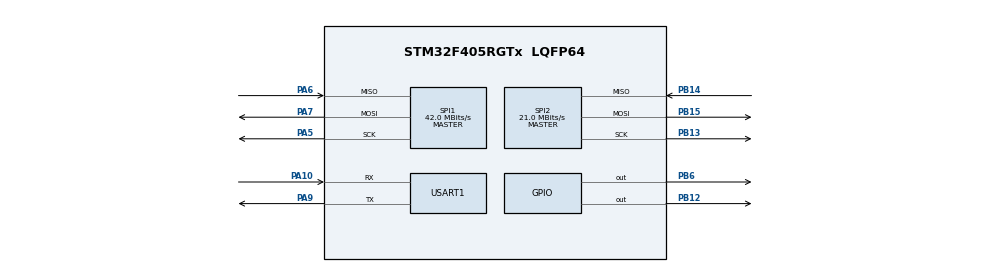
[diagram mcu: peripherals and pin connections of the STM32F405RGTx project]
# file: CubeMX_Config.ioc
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Mcu.Family=STM32F4
Mcu.Name=STM32F405RGTx
Mcu.Package=LQFP64
NVIC.PriorityGroup=NVIC_PRIORITYGROUP_4
PA10.Mode=Asynchronous
PA10.Signal=USART1_RX
PA13.Mode=Serial_Wire
PA13.Signal=SYS_JTMS-SWDIO
PA14.Mode=Serial_Wire
PA14.Signal=SYS_JTCK-SWCLK
PA5.Mode=Full_Duplex_Master
PA5.Signal=SPI1_SCK
PA6.Mode=Full_Duplex_Master
PA6.Signal=SPI1_MISO
PA7.Mode=Full_Duplex_Master
PA7.Signal=SPI1_MOSI
PA9.Mode=Asynchronous
PA9.Signal=USART1_TX
PB12.Signal=GPIO_Output
PB13.Mode=Full_Duplex_Master
PB13.Signal=SPI2_SCK
PB14.Mode=Full_Duplex_Master
PB14.Signal=SPI2_MISO
PB15.Mode=Full_Duplex_Master
PB15.Signal=SPI2_MOSI
PB6.Signal=GPIO_Output
PC14-OSC32_IN.Mode=LSE-External-Oscillator
PC14-OSC32_IN.Signal=RCC_OSC32_IN
PC15-OSC32_OUT.Mode=LSE-External-Oscillator
PC15-OSC32_OUT.Signal=RCC_OSC32_OUT
PH0-OSC_IN.Mode=HSE-External-Oscillator
PH0-OSC_IN.Signal=RCC_OSC_IN
PH1-OSC_OUT.Mode=HSE-External-Oscillator
PH1-OSC_OUT.Signal=RCC_OSC_OUT
ProjectManager.HeapSize=0x200
ProjectManager.StackSize=0x400
ProjectManager.TargetToolchain=MDK-ARM V5
RCC.48MHZClocksFreq_Value=84000000
RCC.AHBFreq_Value=168000000
RCC.APB1CLKDivider=RCC_HCLK_DIV4
RCC.APB1Freq_Value=42000000
RCC.APB1TimFreq_Value=84000000
RCC.APB2CLKDivider=RCC_HCLK_DIV2
RCC.APB2Freq_Value=84000000
RCC.APB2TimFreq_Value=168000000
RCC.CortexFreq_Value=168000000
RCC.HCLKFreq_Value=168000000
RCC.HSE_VALUE=8000000
RCC.HSI_VALUE=16000000
RCC.PLLM=4
RCC.PLLN=168
RCC.PLLSourceVirtual=RCC_PLLSOURCE_HSE
RCC.RCC_RTC_Clock_SourceVirtual=RCC_RTCCLKSOURCE_LSE
RCC.SYSCLKFreq_VALUE=168000000
RCC.SYSCLKSource=RCC_SYSCLKSOURCE_PLLCLK
RCC.VCOOutputFreq_Value=336000000
SPI1.BaudRatePrescaler=SPI_BAUDRATEPRESCALER_2
SPI1.CalculateBaudRate=42.0 MBits/s
SPI1.Direction=SPI_DIRECTION_2LINES
SPI1.Mode=SPI_MODE_MASTER
SPI1.VirtualType=VM_MASTER
SPI2.BaudRatePrescaler=SPI_BAUDRATEPRESCALER_2
SPI2.CalculateBaudRate=21.0 MBits/s
SPI2.Direction=SPI_DIRECTION_2LINES
SPI2.Mode=SPI_MODE_MASTER
SPI2.VirtualType=VM_MASTER
USART1.VirtualMode=VM_ASYNC
VP_IWDG_VS_IWDG.Mode=IWDG_Activate
VP_RTC_VS_RTC_Activate.Mode=RTC_Enabled
board=custom

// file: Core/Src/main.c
/* USER CODE BEGIN Header */
/**
  ******************************************************************************
  * @file           : main.c
  * @brief          : Main program body
  ******************************************************************************
  * @attention
  *
  * Copyright (c) 2022 STMicroelectronics.
  * All rights reserved.
  *
  * This software is licensed under terms that can be found in the LICENSE file
  * in the root directory of this software component.
  * If no LICENSE file comes with this software, it is provided AS-IS.
  *
  ******************************************************************************
  */
/* USER CODE END Header */
#include "main.h"

 IWDG_HandleTypeDef hiwdg;

RTC_HandleTypeDef hrtc;

SPI_HandleTypeDef hspi1;
SPI_HandleTypeDef hspi2;

UART_HandleTypeDef huart1;

void SystemClock_Config(void);
static void MX_GPIO_Init(void);
static void MX_SPI1_Init(void);
static void MX_SPI2_Init(void);
static void MX_USART1_UART_Init(void);
static void MX_IWDG_Init(void);
static void MX_RTC_Init(void);

int main(void)
{

  /* MCU Configuration--------------------------------------------------------*/

  /* Reset of all peripherals, Initializes the Flash interface and the Systick. */
  HAL_Init();

  /* Configure the system clock */
  SystemClock_Config();

  /* Initialize all configured peripherals */
  MX_GPIO_Init();
  MX_SPI1_Init();
  MX_SPI2_Init();
  MX_USART1_UART_Init();
  MX_IWDG_Init();
  MX_RTC_Init();

  /* Infinite loop */
  while (1)
  {

  }
}

void SystemClock_Config(void)
{
  RCC_OscInitTypeDef RCC_OscInitStruct = {0};
  RCC_ClkInitTypeDef RCC_ClkInitStruct = {0};

  /** Configure the main internal regulator output voltage
  */
  __HAL_RCC_PWR_CLK_ENABLE();
  __HAL_PWR_VOLTAGESCALING_CONFIG(PWR_REGULATOR_VOLTAGE_SCALE1);

  /** Initializes the RCC Oscillators according to the specified parameters
  * in the RCC_OscInitTypeDef structure.
  */
  RCC_OscInitStruct.OscillatorType = RCC_OSCILLATORTYPE_LSI|RCC_OSCILLATORTYPE_HSE;
  RCC_OscInitStruct.HSEState = RCC_HSE_ON;
  RCC_OscInitStruct.LSIState = RCC_LSI_ON;
  RCC_OscInitStruct.PLL.PLLState = RCC_PLL_ON;
  RCC_OscInitStruct.PLL.PLLSource = RCC_PLLSOURCE_HSE;
  RCC_OscInitStruct.PLL.PLLM = 4;
  RCC_OscInitStruct.PLL.PLLN = 192;
  RCC_OscInitStruct.PLL.PLLP = RCC_PLLP_DIV4;
  RCC_OscInitStruct.PLL.PLLQ = 4;
  if (HAL_RCC_OscConfig(&RCC_OscInitStruct) != HAL_OK)
  {
    Error_Handler();
  }

  /** Initializes the CPU, AHB and APB buses clocks
  */
  RCC_ClkInitStruct.ClockType = RCC_CLOCKTYPE_HCLK|RCC_CLOCKTYPE_SYSCLK
                              |RCC_CLOCKTYPE_PCLK1|RCC_CLOCKTYPE_PCLK2;
  RCC_ClkInitStruct.SYSCLKSource = RCC_SYSCLKSOURCE_PLLCLK;
  RCC_ClkInitStruct.AHBCLKDivider = RCC_SYSCLK_DIV1;
  RCC_ClkInitStruct.APB1CLKDivider = RCC_HCLK_DIV4;
  RCC_ClkInitStruct.APB2CLKDivider = RCC_HCLK_DIV2;

  if (HAL_RCC_ClockConfig(&RCC_ClkInitStruct, FLASH_LATENCY_3) != HAL_OK)
  {
    Error_Handler();
  }
}

static void MX_IWDG_Init(void)
{

  hiwdg.Instance = IWDG;
  hiwdg.Init.Prescaler = IWDG_PRESCALER_4;
  hiwdg.Init.Reload = 4095;
  if (HAL_IWDG_Init(&hiwdg) != HAL_OK)
  {
    Error_Handler();
  }

}

static void MX_RTC_Init(void)
{

  /** Initialize RTC Only
  */
  hrtc.Instance = RTC;
  hrtc.Init.HourFormat = RTC_HOURFORMAT_24;
  hrtc.Init.AsynchPrediv = 127;
  hrtc.Init.SynchPrediv = 255;
  hrtc.Init.OutPut = RTC_OUTPUT_DISABLE;
  hrtc.Init.OutPutPolarity = RTC_OUTPUT_POLARITY_HIGH;
  hrtc.Init.OutPutType = RTC_OUTPUT_TYPE_OPENDRAIN;
  if (HAL_RTC_Init(&hrtc) != HAL_OK)
  {
    Error_Handler();
  }

}

static void MX_SPI1_Init(void)
{

  /* SPI1 parameter configuration*/
  hspi1.Instance = SPI1;
  hspi1.Init.Mode = SPI_MODE_MASTER;
  hspi1.Init.Direction = SPI_DIRECTION_2LINES;
  hspi1.Init.DataSize = SPI_DATASIZE_8BIT;
  hspi1.Init.CLKPolarity = SPI_POLARITY_LOW;
  hspi1.Init.CLKPhase = SPI_PHASE_1EDGE;
  hspi1.Init.NSS = SPI_NSS_SOFT;
  hspi1.Init.BaudRatePrescaler = SPI_BAUDRATEPRESCALER_2;
  hspi1.Init.FirstBit = SPI_FIRSTBIT_MSB;
  hspi1.Init.TIMode = SPI_TIMODE_DISABLE;
  hspi1.Init.CRCCalculation = SPI_CRCCALCULATION_DISABLE;
  hspi1.Init.CRCPolynomial = 10;
  if (HAL_SPI_Init(&hspi1) != HAL_OK)
  {
    Error_Handler();
  }

}

static void MX_SPI2_Init(void)
{

  /* SPI2 parameter configuration*/
  hspi2.Instance = SPI2;
  hspi2.Init.Mode = SPI_MODE_MASTER;
  hspi2.Init.Direction = SPI_DIRECTION_2LINES;
  hspi2.Init.DataSize = SPI_DATASIZE_8BIT;
  hspi2.Init.CLKPolarity = SPI_POLARITY_LOW;
  hspi2.Init.CLKPhase = SPI_PHASE_1EDGE;
  hspi2.Init.NSS = SPI_NSS_SOFT;
  hspi2.Init.BaudRatePrescaler = SPI_BAUDRATEPRESCALER_2;
  hspi2.Init.FirstBit = SPI_FIRSTBIT_MSB;
  hspi2.Init.TIMode = SPI_TIMODE_DISABLE;
  hspi2.Init.CRCCalculation = SPI_CRCCALCULATION_DISABLE;
  hspi2.Init.CRCPolynomial = 10;
  if (HAL_SPI_Init(&hspi2) != HAL_OK)
  {
    Error_Handler();
  }

}

static void MX_USART1_UART_Init(void)
{

  huart1.Instance = USART1;
  huart1.Init.BaudRate = 115200;
  huart1.Init.WordLength = UART_WORDLENGTH_8B;
  huart1.Init.StopBits = UART_STOPBITS_1;
  huart1.Init.Parity = UART_PARITY_NONE;
  huart1.Init.Mode = UART_MODE_TX_RX;
  huart1.Init.HwFlowCtl = UART_HWCONTROL_NONE;
  huart1.Init.OverSampling = UART_OVERSAMPLING_16;
  if (HAL_UART_Init(&huart1) != HAL_OK)
  {
    Error_Handler();
  }

}

static void MX_GPIO_Init(void)
{
  GPIO_InitTypeDef GPIO_InitStruct = {0};

  /* GPIO Ports Clock Enable */
  __HAL_RCC_GPIOC_CLK_ENABLE();
  __HAL_RCC_GPIOH_CLK_ENABLE();
  __HAL_RCC_GPIOA_CLK_ENABLE();
  __HAL_RCC_GPIOB_CLK_ENABLE();

  /*Configure GPIO pin Output Level */
  HAL_GPIO_WritePin(GPIOB, GPIO_PIN_12|GPIO_PIN_6, GPIO_PIN_RESET);

  /*Configure GPIO pins : PB12 PB6 */
  GPIO_InitStruct.Pin = GPIO_PIN_12|GPIO_PIN_6;
  GPIO_InitStruct.Mode = GPIO_MODE_OUTPUT_PP;
  GPIO_InitStruct.Pull = GPIO_NOPULL;
  GPIO_InitStruct.Speed = GPIO_SPEED_FREQ_LOW;
  HAL_GPIO_Init(GPIOB, &GPIO_InitStruct);

}

void Error_Handler(void)
{
  __disable_irq();
  while (1)
  {
  }
}
